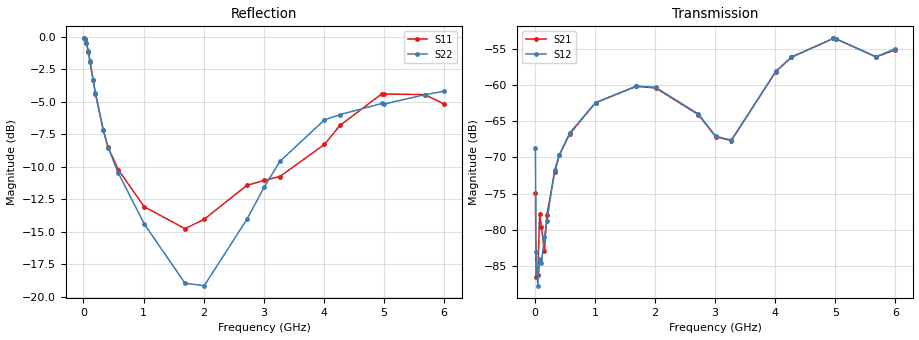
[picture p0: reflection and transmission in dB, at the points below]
!Agilent Technologies,N5230A,MY45001650,A.07.50.48
!Agilent N5230A: A.07.50.48
!Date: Saturday, July 08, 2017 15:50:01
!Correction: S11(Full 2 Port(1,2))
!S21(Full 2 Port(1,2))
!S12(Full 2 Port(1,2))
!S22(Full 2 Port(1,2))
!S2P File: Measurements: S11, S21, S12, S22:
# Hz S  dB  R 50
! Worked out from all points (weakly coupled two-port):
!   600 points, 10 MHz to 6 GHz, reference 50 ohm
!   highest |S21| = -53.57 dB at 4.97 GHz (marker M1); lowest = -86.5 dB at 20 MHz (marker M2)
!   lowest |S11| = -14.8 dB at 1.69 GHz (marker M3), VSWR 1.45, Z = 34.6 + j1.18 ohm
!   |S11| at or under -10 dB: 553.2 MHz to 3.663 GHz (3.11 GHz wide, 148 % of centre)
!   |S22| runs from -19.6 to -0.1 dB; largest |S21 - S12| = 0.00053
!   S11 on the Smith chart (normalised r, x): 10 MHz: 2, -20; 110 MHz: 0.52, -1.89; 330 MHz: 0.55, -0.56; 2.72 GHz: 0.58, +0.09; 4.27 GHz: 1.39, +1.14; 6 GHz: 2.58, -1.43
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1e7  -0.11 -5.7  -74.96 -34.0  -68.73 122.3  -0.11 -5.5
2e7  -0.16 -11.1  -86.53 -135.2  -83.02 -142.2  -0.14 -10.5
5e7  -0.50 -26.6  -86.28 -104.2  -87.72 111.4  -0.48 -25.4
8e7  -1.13 -40.8  -77.84 165.5  -84.09 63.1  -1.10 -38.9
1.1e8  -1.91 -53.1  -79.62 -84.1  -84.54 108.9  -1.88 -50.6
1.6e8  -3.31 -70.0  -82.95 128.6  -80.95 125.2  -3.29 -66.6
2e8  -4.38 -81.2  -77.94 123.2  -78.85 115.3  -4.34 -77.2
3.3e8  -7.18 -109.0  -72.09 99.1  -71.72 96.2  -7.18 -101.8
4.1e8  -8.51 -121.9  -69.65 88.1  -69.65 87.3  -8.52 -112.9
5.8e8  -10.23 -143.1  -66.78 70.4  -66.63 70.3  -10.48 -130.7
1.01e9  -13.07 -172.4  -62.46 37.2  -62.45 37.0  -14.39 -154.8
1.69e9  -14.77 174.8  -60.20 -10.4  -60.15 -10.4  -18.97 -170.6
2.01e9  -14.04 177.0  -60.42 -34.1  -60.33 -34.2  -19.16 -169.6
2.72e9  -11.43 163.9  -64.09 -97.6  -64.00 -96.2  -14.05 177.0
3.01e9  -11.05 149.5  -67.15 -143.7  -67.08 -142.9  -11.55 168.4
3.27e9  -10.75 131.5  -67.70 156.8  -67.63 156.0  -9.58 160.7
4.01e9  -8.28 64.2  -58.16 44.0  -58.14 44.3  -6.39 139.8
4.27e9  -6.81 45.7  -56.19 19.5  -56.15 18.9  -5.98 131.5
4.97e9  -4.37 14.7  -53.57 -40.7  -53.58 -41.2  -5.12 104.2
5.01e9  -4.40 13.1  -53.63 -44.5  -53.64 -44.8  -5.16 102.3
5.68e9  -4.44 -7.6  -56.14 -76.8  -56.11 -76.5  -4.45 69.2
6e9  -5.16 -20.4  -55.14 -75.9  -55.00 -76.4  -4.18 52.3
